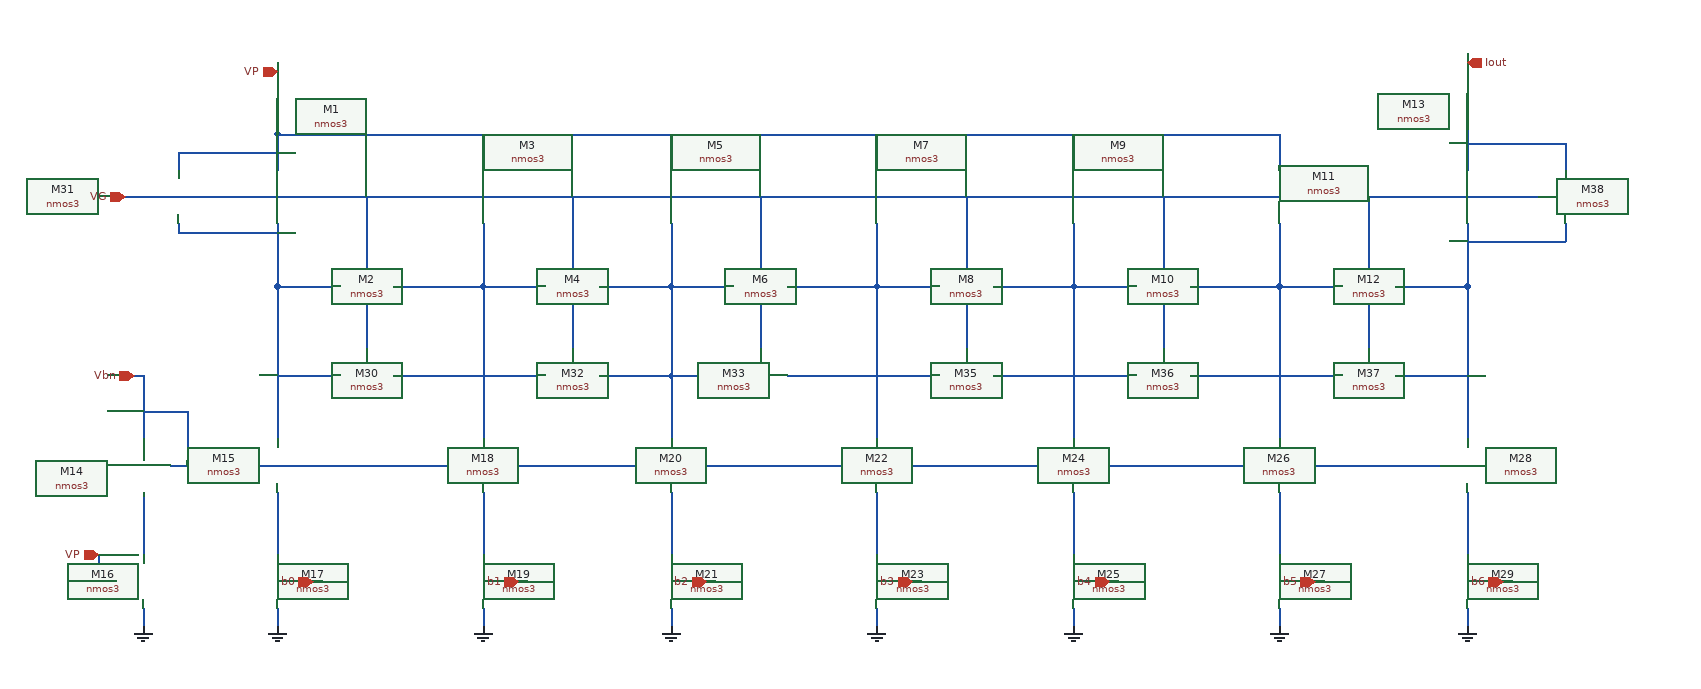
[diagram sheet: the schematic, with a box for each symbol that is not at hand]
v {xschem version=2.9.9 file_version=1.2 }
G {}
K {}
V {}
S {}
E {}
N 220 -610 250 -610 { lab=b0}
N 280 -580 280 -510 { lab=#net1}
N 280 -510 350 -510 { lab=#net1}
N 410 -510 510 -510 { lab=#net2}
N 510 -580 510 -510 { lab=#net2}
N 510 -510 580 -510 { lab=#net2}
N 250 -610 480 -610 { lab=b0}
N 380 -610 380 -540 { lab=b0}
N 280 -510 280 -380 { lab=#net1}
N 510 -510 510 -380 { lab=#net2}
N 720 -580 720 -510 { lab=#net3}
N 720 -510 790 -510 { lab=#net3}
N 850 -510 950 -510 { lab=#net4}
N 950 -580 950 -510 { lab=#net4}
N 950 -510 1020 -510 { lab=#net4}
N 690 -610 920 -610 { lab=b0}
N 820 -610 820 -540 { lab=b0}
N 720 -510 720 -380 { lab=#net3}
N 950 -510 950 -380 { lab=#net4}
N 480 -610 690 -610 { lab=b0}
N 640 -510 720 -510 { lab=#net3}
N 1110 -610 1140 -610 { lab=b0}
N 1170 -580 1170 -510 { lab=#net5}
N 1170 -510 1240 -510 { lab=#net5}
N 1300 -510 1400 -510 { lab=#net6}
N 1400 -580 1400 -510 { lab=#net6}
N 1400 -510 1470 -510 { lab=#net6}
N 1140 -610 1370 -610 { lab=b0}
N 1270 -610 1270 -540 { lab=b0}
N 1170 -510 1170 -380 { lab=#net5}
N 1400 -510 1400 -380 { lab=#net6}
N 1610 -580 1610 -510 { lab=#net7}
N 1610 -510 1610 -380 { lab=#net7}
N 1370 -610 1580 -610 { lab=b0}
N 1530 -510 1610 -510 { lab=#net7}
N 920 -610 1110 -610 { lab=b0}
N 1080 -510 1170 -510 { lab=#net5}
N 130 -280 130 -210 { lab=#net8}
N 160 -310 250 -310 { lab=Vbn}
N 130 -380 130 -340 { lab=Vbn}
N 130 -370 180 -370 { lab=Vbn}
N 180 -370 180 -310 { lab=Vbn}
N 280 -280 280 -210 { lab=#net9}
N 130 -150 130 -130 { lab=GND}
N 280 -150 280 -130 { lab=GND}
N 80 -200 80 -180 { lab=VP}
N 80 -180 100 -180 { lab=VP}
N 130 -390 130 -380 { lab=Vbn}
N 70 -210 80 -210 { lab=VP}
N 80 -210 80 -200 { lab=VP}
N 110 -410 130 -410 { lab=Vbn}
N 130 -410 130 -390 { lab=Vbn}
N 280 -380 280 -340 { lab=#net1}
N 510 -280 510 -210 { lab=#net10}
N 510 -150 510 -130 { lab=GND}
N 510 -380 510 -340 { lab=#net2}
N 250 -310 480 -310 { lab=Vbn}
N 720 -280 720 -210 { lab=#net11}
N 720 -150 720 -130 { lab=GND}
N 690 -310 920 -310 { lab=Vbn}
N 950 -280 950 -210 { lab=#net12}
N 950 -150 950 -130 { lab=GND}
N 920 -310 1150 -310 { lab=Vbn}
N 480 -310 690 -310 { lab=Vbn}
N 720 -380 720 -340 { lab=#net3}
N 950 -380 950 -340 { lab=#net4}
N 1170 -280 1170 -210 { lab=#net13}
N 1170 -150 1170 -130 { lab=GND}
N 1170 -380 1170 -340 { lab=#net5}
N 1400 -280 1400 -210 { lab=#net14}
N 1400 -150 1400 -130 { lab=GND}
N 1400 -380 1400 -340 { lab=#net6}
N 1150 -310 1370 -310 { lab=Vbn}
N 1610 -280 1610 -210 { lab=#net15}
N 1610 -150 1610 -130 { lab=GND}
N 1370 -310 1580 -310 { lab=Vbn}
N 1610 -380 1610 -340 { lab=#net7}
N 280 -680 280 -640 { lab=VP}
N 510 -680 510 -640 { lab=VP}
N 720 -680 720 -640 { lab=VP}
N 950 -680 950 -640 { lab=VP}
N 1170 -680 1170 -640 { lab=VP}
N 1400 -680 1400 -640 { lab=VP}
N 1050 -610 1050 -540 { lab=b0}
N 610 -610 610 -540 { lab=b0}
N 1500 -610 1500 -540 { lab=b0}
N 1610 -770 1610 -640 { lab=Iout}
N 1640 -180 1660 -180 { lab=b6}
N 1430 -180 1450 -180 { lab=b5}
N 1200 -180 1220 -180 { lab=b4}
N 980 -180 1000 -180 { lab=b3}
N 750 -180 770 -180 { lab=b2}
N 540 -180 560 -180 { lab=b1}
N 310 -180 330 -180 { lab=b0}
N 280 -680 1400 -680 { lab=VP}
N 280 -760 280 -680 { lab=VP}
N 280 -410 350 -410 { lab=#net1}
N 410 -410 510 -410 { lab=#net2}
N 380 -540 380 -440 { lab=b0}
N 100 -610 140 -610 { lab=b0}
N 170 -580 170 -570 { lab=#net1}
N 170 -570 280 -570 { lab=#net1}
N 170 -660 170 -640 { lab=VP}
N 170 -660 280 -660 { lab=VP}
N 140 -610 220 -610 { lab=b0}
N 510 -410 580 -410 { lab=#net2}
N 610 -540 610 -440 { lab=b0}
N 640 -410 720 -410 { lab=#net3}
N 720 -410 790 -410 { lab=#net3}
N 820 -540 820 -440 { lab=b0}
N 850 -410 950 -410 { lab=#net4}
N 720 -410 790 -410 { lab=#net3}
N 1050 -540 1050 -440 { lab=b0}
N 950 -410 1020 -410 { lab=#net4}
N 1270 -540 1270 -440 { lab=b0}
N 1300 -410 1400 -410 { lab=#net6}
N 1170 -410 1240 -410 { lab=#net5}
N 1500 -540 1500 -440 { lab=b0}
N 1400 -410 1470 -410 { lab=#net6}
N 1080 -410 1170 -410 { lab=#net5}
N 1530 -410 1610 -410 { lab=#net7}
N 1720 -670 1720 -640 { lab=Iout}
N 1610 -670 1720 -670 { lab=Iout}
N 1580 -610 1690 -610 { lab=b0}
N 1610 -560 1720 -560 { lab=#net7}
N 1720 -580 1720 -560 { lab=#net7}
C {madvlsi/nmos3.sym} 280 -610 0 0 {name=M1
L=4
W=0.75
body=GND
nf=1
mult=1
ad="'int((nf+1)/2) * W/nf * 0.29'" 
pd="'2*int((nf+1)/2) * (W/nf + 0.29)'"
as="'int((nf+2)/2) * W/nf * 0.29'" 
ps="'2*int((nf+2)/2) * (W/nf + 0.29)'"
nrd="'0.29 / W'" nrs="'0.29 / W'"
sa=0 sb=0 sd=0
model=nfet_01v8
spiceprefix=X
}
C {madvlsi/nmos3.sym} 380 -510 1 0 {name=M2
L=4
W=0.75
body=GND
nf=1
mult=1
ad="'int((nf+1)/2) * W/nf * 0.29'" 
pd="'2*int((nf+1)/2) * (W/nf + 0.29)'"
as="'int((nf+2)/2) * W/nf * 0.29'" 
ps="'2*int((nf+2)/2) * (W/nf + 0.29)'"
nrd="'0.29 / W'" nrs="'0.29 / W'"
sa=0 sb=0 sd=0
model=nfet_01v8
spiceprefix=X
}
C {madvlsi/nmos3.sym} 510 -610 0 0 {name=M3
L=4
W=0.75
body=GND
nf=1
mult=1
ad="'int((nf+1)/2) * W/nf * 0.29'" 
pd="'2*int((nf+1)/2) * (W/nf + 0.29)'"
as="'int((nf+2)/2) * W/nf * 0.29'" 
ps="'2*int((nf+2)/2) * (W/nf + 0.29)'"
nrd="'0.29 / W'" nrs="'0.29 / W'"
sa=0 sb=0 sd=0
model=nfet_01v8
spiceprefix=X
}
C {madvlsi/nmos3.sym} 610 -510 1 0 {name=M4
L=4
W=0.75
body=GND
nf=1
mult=1
ad="'int((nf+1)/2) * W/nf * 0.29'" 
pd="'2*int((nf+1)/2) * (W/nf + 0.29)'"
as="'int((nf+2)/2) * W/nf * 0.29'" 
ps="'2*int((nf+2)/2) * (W/nf + 0.29)'"
nrd="'0.29 / W'" nrs="'0.29 / W'"
sa=0 sb=0 sd=0
model=nfet_01v8
spiceprefix=X
}
C {madvlsi/nmos3.sym} 720 -610 0 0 {name=M5
L=4
W=0.75
body=GND
nf=1
mult=1
ad="'int((nf+1)/2) * W/nf * 0.29'" 
pd="'2*int((nf+1)/2) * (W/nf + 0.29)'"
as="'int((nf+2)/2) * W/nf * 0.29'" 
ps="'2*int((nf+2)/2) * (W/nf + 0.29)'"
nrd="'0.29 / W'" nrs="'0.29 / W'"
sa=0 sb=0 sd=0
model=nfet_01v8
spiceprefix=X
}
C {madvlsi/nmos3.sym} 820 -510 1 0 {name=M6
L=4
W=0.75
body=GND
nf=1
mult=1
ad="'int((nf+1)/2) * W/nf * 0.29'" 
pd="'2*int((nf+1)/2) * (W/nf + 0.29)'"
as="'int((nf+2)/2) * W/nf * 0.29'" 
ps="'2*int((nf+2)/2) * (W/nf + 0.29)'"
nrd="'0.29 / W'" nrs="'0.29 / W'"
sa=0 sb=0 sd=0
model=nfet_01v8
spiceprefix=X
}
C {madvlsi/nmos3.sym} 950 -610 0 0 {name=M7
L=4
W=0.75
body=GND
nf=1
mult=1
ad="'int((nf+1)/2) * W/nf * 0.29'" 
pd="'2*int((nf+1)/2) * (W/nf + 0.29)'"
as="'int((nf+2)/2) * W/nf * 0.29'" 
ps="'2*int((nf+2)/2) * (W/nf + 0.29)'"
nrd="'0.29 / W'" nrs="'0.29 / W'"
sa=0 sb=0 sd=0
model=nfet_01v8
spiceprefix=X
}
C {madvlsi/nmos3.sym} 1050 -510 1 0 {name=M8
L=4
W=0.75
body=GND
nf=1
mult=1
ad="'int((nf+1)/2) * W/nf * 0.29'" 
pd="'2*int((nf+1)/2) * (W/nf + 0.29)'"
as="'int((nf+2)/2) * W/nf * 0.29'" 
ps="'2*int((nf+2)/2) * (W/nf + 0.29)'"
nrd="'0.29 / W'" nrs="'0.29 / W'"
sa=0 sb=0 sd=0
model=nfet_01v8
spiceprefix=X
}
C {madvlsi/nmos3.sym} 1170 -610 0 0 {name=M9
L=4
W=0.75
body=GND
nf=1
mult=1
ad="'int((nf+1)/2) * W/nf * 0.29'" 
pd="'2*int((nf+1)/2) * (W/nf + 0.29)'"
as="'int((nf+2)/2) * W/nf * 0.29'" 
ps="'2*int((nf+2)/2) * (W/nf + 0.29)'"
nrd="'0.29 / W'" nrs="'0.29 / W'"
sa=0 sb=0 sd=0
model=nfet_01v8
spiceprefix=X
}
C {madvlsi/nmos3.sym} 1270 -510 1 0 {name=M10
L=4
W=0.75
body=GND
nf=1
mult=1
ad="'int((nf+1)/2) * W/nf * 0.29'" 
pd="'2*int((nf+1)/2) * (W/nf + 0.29)'"
as="'int((nf+2)/2) * W/nf * 0.29'" 
ps="'2*int((nf+2)/2) * (W/nf + 0.29)'"
nrd="'0.29 / W'" nrs="'0.29 / W'"
sa=0 sb=0 sd=0
model=nfet_01v8
spiceprefix=X
}
C {madvlsi/nmos3.sym} 1400 -610 0 0 {name=M11
L=4
W=0.75
body=GND
nf=1
mult=1
ad="'int((nf+1)/2) * W/nf * 0.29'" 
pd="'2*int((nf+1)/2) * (W/nf + 0.29)'"
as="'int((nf+2)/2) * W/nf * 0.29'" 
ps="'2*int((nf+2)/2) * (W/nf + 0.29)'"
nrd="'0.29 / W'" nrs="'0.29 / W'"
sa=0 sb=0 sd=0
model=nfet_01v8
spiceprefix=X
}
C {madvlsi/nmos3.sym} 1500 -510 1 0 {name=M12
L=4
W=0.75
body=GND
nf=1
mult=1
ad="'int((nf+1)/2) * W/nf * 0.29'" 
pd="'2*int((nf+1)/2) * (W/nf + 0.29)'"
as="'int((nf+2)/2) * W/nf * 0.29'" 
ps="'2*int((nf+2)/2) * (W/nf + 0.29)'"
nrd="'0.29 / W'" nrs="'0.29 / W'"
sa=0 sb=0 sd=0
model=nfet_01v8
spiceprefix=X
}
C {madvlsi/nmos3.sym} 1610 -610 0 0 {name=M13
L=4
W=0.75
body=GND
nf=1
mult=1
ad="'int((nf+1)/2) * W/nf * 0.29'" 
pd="'2*int((nf+1)/2) * (W/nf + 0.29)'"
as="'int((nf+2)/2) * W/nf * 0.29'" 
ps="'2*int((nf+2)/2) * (W/nf + 0.29)'"
nrd="'0.29 / W'" nrs="'0.29 / W'"
sa=0 sb=0 sd=0
model=nfet_01v8
spiceprefix=X
}
C {madvlsi/nmos3.sym} 130 -310 2 0 {name=M14
L=4
W=0.75
body=GND
nf=1
mult=1
ad="'int((nf+1)/2) * W/nf * 0.29'" 
pd="'2*int((nf+1)/2) * (W/nf + 0.29)'"
as="'int((nf+2)/2) * W/nf * 0.29'" 
ps="'2*int((nf+2)/2) * (W/nf + 0.29)'"
nrd="'0.29 / W'" nrs="'0.29 / W'"
sa=0 sb=0 sd=0
model=nfet_01v8
spiceprefix=X
}
C {madvlsi/nmos3.sym} 280 -310 0 0 {name=M15
L=4
W=0.75
body=GND
nf=1
mult=1
ad="'int((nf+1)/2) * W/nf * 0.29'" 
pd="'2*int((nf+1)/2) * (W/nf + 0.29)'"
as="'int((nf+2)/2) * W/nf * 0.29'" 
ps="'2*int((nf+2)/2) * (W/nf + 0.29)'"
nrd="'0.29 / W'" nrs="'0.29 / W'"
sa=0 sb=0 sd=0
model=nfet_01v8
spiceprefix=X
}
C {madvlsi/nmos3.sym} 130 -180 0 0 {name=M16
L=0.15
W=1
body=GND
nf=1
mult=1
ad="'int((nf+1)/2) * W/nf * 0.29'" 
pd="'2*int((nf+1)/2) * (W/nf + 0.29)'"
as="'int((nf+2)/2) * W/nf * 0.29'" 
ps="'2*int((nf+2)/2) * (W/nf + 0.29)'"
nrd="'0.29 / W'" nrs="'0.29 / W'"
sa=0 sb=0 sd=0
model=nfet_01v8
spiceprefix=X
}
C {madvlsi/nmos3.sym} 280 -180 2 0 {name=M17
L=0.15
W=1
body=GND
nf=1
mult=1
ad="'int((nf+1)/2) * W/nf * 0.29'" 
pd="'2*int((nf+1)/2) * (W/nf + 0.29)'"
as="'int((nf+2)/2) * W/nf * 0.29'" 
ps="'2*int((nf+2)/2) * (W/nf + 0.29)'"
nrd="'0.29 / W'" nrs="'0.29 / W'"
sa=0 sb=0 sd=0
model=nfet_01v8
spiceprefix=X
}
C {madvlsi/gnd.sym} 130 -130 0 0 {name=l1 lab=GND}
C {madvlsi/gnd.sym} 280 -130 0 0 {name=l2 lab=GND}
C {devices/iopin.sym} 80 -210 2 0 {name=p2 lab=VP}
C {madvlsi/nmos3.sym} 510 -310 0 0 {name=M18
L=4
W=0.75
body=GND
nf=1
mult=1
ad="'int((nf+1)/2) * W/nf * 0.29'" 
pd="'2*int((nf+1)/2) * (W/nf + 0.29)'"
as="'int((nf+2)/2) * W/nf * 0.29'" 
ps="'2*int((nf+2)/2) * (W/nf + 0.29)'"
nrd="'0.29 / W'" nrs="'0.29 / W'"
sa=0 sb=0 sd=0
model=nfet_01v8
spiceprefix=X
}
C {madvlsi/nmos3.sym} 510 -180 2 0 {name=M19
L=0.15
W=1
body=GND
nf=1
mult=1
ad="'int((nf+1)/2) * W/nf * 0.29'" 
pd="'2*int((nf+1)/2) * (W/nf + 0.29)'"
as="'int((nf+2)/2) * W/nf * 0.29'" 
ps="'2*int((nf+2)/2) * (W/nf + 0.29)'"
nrd="'0.29 / W'" nrs="'0.29 / W'"
sa=0 sb=0 sd=0
model=nfet_01v8
spiceprefix=X
}
C {madvlsi/gnd.sym} 510 -130 0 0 {name=l3 lab=GND}
C {madvlsi/nmos3.sym} 720 -310 0 0 {name=M20
L=4
W=0.75
body=GND
nf=1
mult=1
ad="'int((nf+1)/2) * W/nf * 0.29'" 
pd="'2*int((nf+1)/2) * (W/nf + 0.29)'"
as="'int((nf+2)/2) * W/nf * 0.29'" 
ps="'2*int((nf+2)/2) * (W/nf + 0.29)'"
nrd="'0.29 / W'" nrs="'0.29 / W'"
sa=0 sb=0 sd=0
model=nfet_01v8
spiceprefix=X
}
C {madvlsi/nmos3.sym} 720 -180 2 0 {name=M21
L=0.15
W=1
body=GND
nf=1
mult=1
ad="'int((nf+1)/2) * W/nf * 0.29'" 
pd="'2*int((nf+1)/2) * (W/nf + 0.29)'"
as="'int((nf+2)/2) * W/nf * 0.29'" 
ps="'2*int((nf+2)/2) * (W/nf + 0.29)'"
nrd="'0.29 / W'" nrs="'0.29 / W'"
sa=0 sb=0 sd=0
model=nfet_01v8
spiceprefix=X
}
C {madvlsi/gnd.sym} 720 -130 0 0 {name=l4 lab=GND}
C {madvlsi/nmos3.sym} 950 -310 0 0 {name=M22
L=4
W=0.75
body=GND
nf=1
mult=1
ad="'int((nf+1)/2) * W/nf * 0.29'" 
pd="'2*int((nf+1)/2) * (W/nf + 0.29)'"
as="'int((nf+2)/2) * W/nf * 0.29'" 
ps="'2*int((nf+2)/2) * (W/nf + 0.29)'"
nrd="'0.29 / W'" nrs="'0.29 / W'"
sa=0 sb=0 sd=0
model=nfet_01v8
spiceprefix=X
}
C {madvlsi/nmos3.sym} 950 -180 2 0 {name=M23
L=0.15
W=1
body=GND
nf=1
mult=1
ad="'int((nf+1)/2) * W/nf * 0.29'" 
pd="'2*int((nf+1)/2) * (W/nf + 0.29)'"
as="'int((nf+2)/2) * W/nf * 0.29'" 
ps="'2*int((nf+2)/2) * (W/nf + 0.29)'"
nrd="'0.29 / W'" nrs="'0.29 / W'"
sa=0 sb=0 sd=0
model=nfet_01v8
spiceprefix=X
}
C {madvlsi/gnd.sym} 950 -130 0 0 {name=l5 lab=GND}
C {madvlsi/nmos3.sym} 1170 -310 0 0 {name=M24
L=4
W=0.75
body=GND
nf=1
mult=1
ad="'int((nf+1)/2) * W/nf * 0.29'" 
pd="'2*int((nf+1)/2) * (W/nf + 0.29)'"
as="'int((nf+2)/2) * W/nf * 0.29'" 
ps="'2*int((nf+2)/2) * (W/nf + 0.29)'"
nrd="'0.29 / W'" nrs="'0.29 / W'"
sa=0 sb=0 sd=0
model=nfet_01v8
spiceprefix=X
}
C {madvlsi/nmos3.sym} 1170 -180 2 0 {name=M25
L=0.15
W=1
body=GND
nf=1
mult=1
ad="'int((nf+1)/2) * W/nf * 0.29'" 
pd="'2*int((nf+1)/2) * (W/nf + 0.29)'"
as="'int((nf+2)/2) * W/nf * 0.29'" 
ps="'2*int((nf+2)/2) * (W/nf + 0.29)'"
nrd="'0.29 / W'" nrs="'0.29 / W'"
sa=0 sb=0 sd=0
model=nfet_01v8
spiceprefix=X
}
C {madvlsi/gnd.sym} 1170 -130 0 0 {name=l6 lab=GND}
C {madvlsi/nmos3.sym} 1400 -310 0 0 {name=M26
L=4
W=0.75
body=GND
nf=1
mult=1
ad="'int((nf+1)/2) * W/nf * 0.29'" 
pd="'2*int((nf+1)/2) * (W/nf + 0.29)'"
as="'int((nf+2)/2) * W/nf * 0.29'" 
ps="'2*int((nf+2)/2) * (W/nf + 0.29)'"
nrd="'0.29 / W'" nrs="'0.29 / W'"
sa=0 sb=0 sd=0
model=nfet_01v8
spiceprefix=X
}
C {madvlsi/nmos3.sym} 1400 -180 2 0 {name=M27
L=0.15
W=1
body=GND
nf=1
mult=1
ad="'int((nf+1)/2) * W/nf * 0.29'" 
pd="'2*int((nf+1)/2) * (W/nf + 0.29)'"
as="'int((nf+2)/2) * W/nf * 0.29'" 
ps="'2*int((nf+2)/2) * (W/nf + 0.29)'"
nrd="'0.29 / W'" nrs="'0.29 / W'"
sa=0 sb=0 sd=0
model=nfet_01v8
spiceprefix=X
}
C {madvlsi/gnd.sym} 1400 -130 0 0 {name=l7 lab=GND}
C {madvlsi/nmos3.sym} 1610 -310 0 0 {name=M28
L=4
W=0.75
body=GND
nf=1
mult=1
ad="'int((nf+1)/2) * W/nf * 0.29'" 
pd="'2*int((nf+1)/2) * (W/nf + 0.29)'"
as="'int((nf+2)/2) * W/nf * 0.29'" 
ps="'2*int((nf+2)/2) * (W/nf + 0.29)'"
nrd="'0.29 / W'" nrs="'0.29 / W'"
sa=0 sb=0 sd=0
model=nfet_01v8
spiceprefix=X
}
C {madvlsi/nmos3.sym} 1610 -180 2 0 {name=M29
L=0.15
W=1
body=GND
nf=1
mult=1
ad="'int((nf+1)/2) * W/nf * 0.29'" 
pd="'2*int((nf+1)/2) * (W/nf + 0.29)'"
as="'int((nf+2)/2) * W/nf * 0.29'" 
ps="'2*int((nf+2)/2) * (W/nf + 0.29)'"
nrd="'0.29 / W'" nrs="'0.29 / W'"
sa=0 sb=0 sd=0
model=nfet_01v8
spiceprefix=X
}
C {madvlsi/gnd.sym} 1610 -130 0 0 {name=l8 lab=GND}
C {devices/ipin.sym} 1650 -180 2 0 {name=p4 lab=b6}
C {devices/ipin.sym} 1440 -180 2 0 {name=p5 lab=b5}
C {devices/ipin.sym} 1210 -180 2 0 {name=p6 lab=b4}
C {devices/ipin.sym} 990 -180 2 0 {name=p7 lab=b3}
C {devices/ipin.sym} 760 -180 2 0 {name=p8 lab=b2}
C {devices/ipin.sym} 550 -180 2 0 {name=p9 lab=b1}
C {devices/ipin.sym} 320 -180 2 0 {name=p10 lab=b0}
C {devices/iopin.sym} 280 -750 3 0 {name=p11 lab=VP}
C {devices/opin.sym} 1610 -760 3 0 {name=p12 lab=Iout}
C {madvlsi/nmos3.sym} 380 -410 1 0 {name=M30
L=4
W=0.75
body=GND
nf=1
mult=1
ad="'int((nf+1)/2) * W/nf * 0.29'" 
pd="'2*int((nf+1)/2) * (W/nf + 0.29)'"
as="'int((nf+2)/2) * W/nf * 0.29'" 
ps="'2*int((nf+2)/2) * (W/nf + 0.29)'"
nrd="'0.29 / W'" nrs="'0.29 / W'"
sa=0 sb=0 sd=0
model=nfet_01v8
spiceprefix=X
}
C {madvlsi/nmos3.sym} 170 -610 0 0 {name=M31
L=4
W=0.75
body=GND
nf=1
mult=1
ad="'int((nf+1)/2) * W/nf * 0.29'" 
pd="'2*int((nf+1)/2) * (W/nf + 0.29)'"
as="'int((nf+2)/2) * W/nf * 0.29'" 
ps="'2*int((nf+2)/2) * (W/nf + 0.29)'"
nrd="'0.29 / W'" nrs="'0.29 / W'"
sa=0 sb=0 sd=0
model=nfet_01v8
spiceprefix=X
}
C {madvlsi/nmos3.sym} 610 -410 1 0 {name=M32
L=4
W=0.75
body=GND
nf=1
mult=1
ad="'int((nf+1)/2) * W/nf * 0.29'" 
pd="'2*int((nf+1)/2) * (W/nf + 0.29)'"
as="'int((nf+2)/2) * W/nf * 0.29'" 
ps="'2*int((nf+2)/2) * (W/nf + 0.29)'"
nrd="'0.29 / W'" nrs="'0.29 / W'"
sa=0 sb=0 sd=0
model=nfet_01v8
spiceprefix=X
}
C {madvlsi/nmos3.sym} 820 -410 1 0 {name=M33
L=4
W=0.75
body=GND
nf=1
mult=1
ad="'int((nf+1)/2) * W/nf * 0.29'" 
pd="'2*int((nf+1)/2) * (W/nf + 0.29)'"
as="'int((nf+2)/2) * W/nf * 0.29'" 
ps="'2*int((nf+2)/2) * (W/nf + 0.29)'"
nrd="'0.29 / W'" nrs="'0.29 / W'"
sa=0 sb=0 sd=0
model=nfet_01v8
spiceprefix=X
}
C {madvlsi/nmos3.sym} 1050 -410 1 0 {name=M35
L=4
W=0.75
body=GND
nf=1
mult=1
ad="'int((nf+1)/2) * W/nf * 0.29'" 
pd="'2*int((nf+1)/2) * (W/nf + 0.29)'"
as="'int((nf+2)/2) * W/nf * 0.29'" 
ps="'2*int((nf+2)/2) * (W/nf + 0.29)'"
nrd="'0.29 / W'" nrs="'0.29 / W'"
sa=0 sb=0 sd=0
model=nfet_01v8
spiceprefix=X
}
C {madvlsi/nmos3.sym} 1270 -410 1 0 {name=M36
L=4
W=0.75
body=GND
nf=1
mult=1
ad="'int((nf+1)/2) * W/nf * 0.29'" 
pd="'2*int((nf+1)/2) * (W/nf + 0.29)'"
as="'int((nf+2)/2) * W/nf * 0.29'" 
ps="'2*int((nf+2)/2) * (W/nf + 0.29)'"
nrd="'0.29 / W'" nrs="'0.29 / W'"
sa=0 sb=0 sd=0
model=nfet_01v8
spiceprefix=X
}
C {madvlsi/nmos3.sym} 1500 -410 1 0 {name=M37
L=4
W=0.75
body=GND
nf=1
mult=1
ad="'int((nf+1)/2) * W/nf * 0.29'" 
pd="'2*int((nf+1)/2) * (W/nf + 0.29)'"
as="'int((nf+2)/2) * W/nf * 0.29'" 
ps="'2*int((nf+2)/2) * (W/nf + 0.29)'"
nrd="'0.29 / W'" nrs="'0.29 / W'"
sa=0 sb=0 sd=0
model=nfet_01v8
spiceprefix=X
}
C {madvlsi/nmos3.sym} 1720 -610 0 0 {name=M38
L=4
W=0.75
body=GND
nf=1
mult=1
ad="'int((nf+1)/2) * W/nf * 0.29'" 
pd="'2*int((nf+1)/2) * (W/nf + 0.29)'"
as="'int((nf+2)/2) * W/nf * 0.29'" 
ps="'2*int((nf+2)/2) * (W/nf + 0.29)'"
nrd="'0.29 / W'" nrs="'0.29 / W'"
sa=0 sb=0 sd=0
model=nfet_01v8
spiceprefix=X
}
C {devices/ipin.sym} 110 -610 0 0 {name=p1 lab=VG}
C {devices/ipin.sym} 120 -410 0 0 {name=p3 lab=Vbn}
